VERSION 5.7 ;
BUSBITCHARS "[]" ;
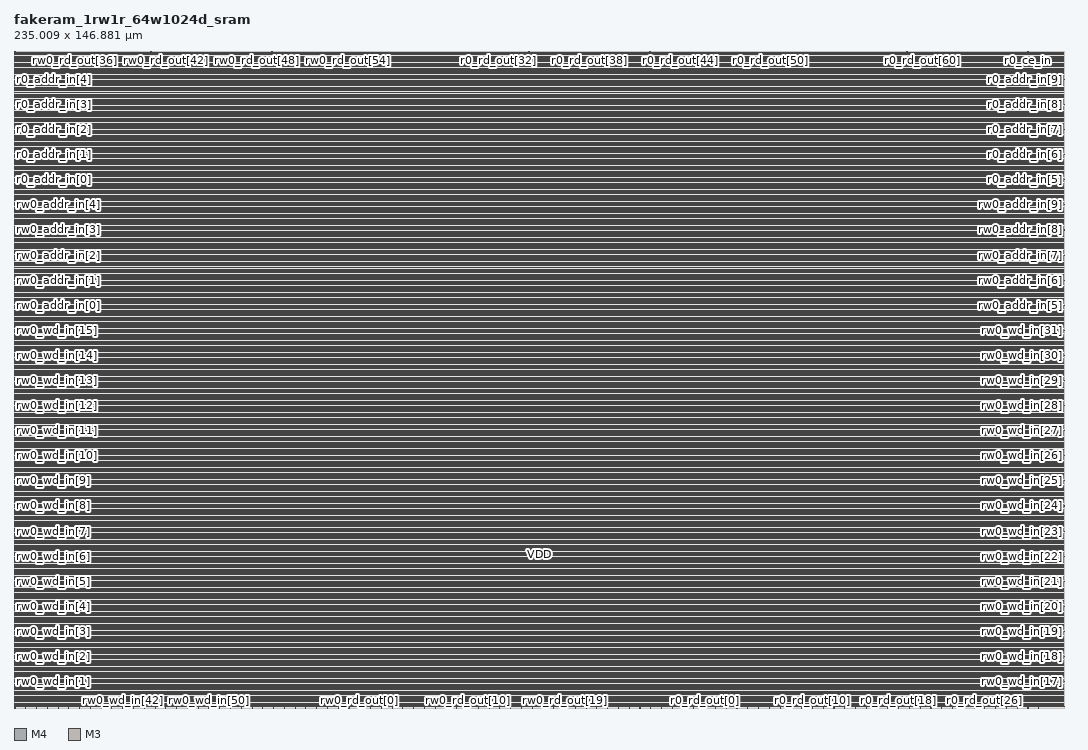
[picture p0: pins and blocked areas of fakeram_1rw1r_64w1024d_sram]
MACRO fakeram_1rw1r_64w1024d_sram
  FOREIGN fakeram_1rw1r_64w1024d_sram 0 0 ;
  SYMMETRY X Y R90 ;
  SIZE 235.009 BY 146.881 ;
  CLASS BLOCK ;
  PIN rw0_wd_in[0]
    DIRECTION INPUT ;
    USE SIGNAL ;
    SHAPE ABUTMENT ;
    PORT
      LAYER M4 ;
      RECT 0.000 0.276 0.072 0.300 ;
    END
  END rw0_wd_in[0]
  PIN rw0_wd_in[1]
    DIRECTION INPUT ;
    USE SIGNAL ;
    SHAPE ABUTMENT ;
    PORT
      LAYER M4 ;
      RECT 0.000 5.892 0.072 5.916 ;
    END
  END rw0_wd_in[1]
  PIN rw0_wd_in[2]
    DIRECTION INPUT ;
    USE SIGNAL ;
    SHAPE ABUTMENT ;
    PORT
      LAYER M4 ;
      RECT 0.000 11.508 0.072 11.532 ;
    END
  END rw0_wd_in[2]
  PIN rw0_wd_in[3]
    DIRECTION INPUT ;
    USE SIGNAL ;
    SHAPE ABUTMENT ;
    PORT
      LAYER M4 ;
      RECT 0.000 17.124 0.072 17.148 ;
    END
  END rw0_wd_in[3]
  PIN rw0_wd_in[4]
    DIRECTION INPUT ;
    USE SIGNAL ;
    SHAPE ABUTMENT ;
    PORT
      LAYER M4 ;
      RECT 0.000 22.740 0.072 22.764 ;
    END
  END rw0_wd_in[4]
  PIN rw0_wd_in[5]
    DIRECTION INPUT ;
    USE SIGNAL ;
    SHAPE ABUTMENT ;
    PORT
      LAYER M4 ;
      RECT 0.000 28.356 0.072 28.380 ;
    END
  END rw0_wd_in[5]
  PIN rw0_wd_in[6]
    DIRECTION INPUT ;
    USE SIGNAL ;
    SHAPE ABUTMENT ;
    PORT
      LAYER M4 ;
      RECT 0.000 33.972 0.072 33.996 ;
    END
  END rw0_wd_in[6]
  PIN rw0_wd_in[7]
    DIRECTION INPUT ;
    USE SIGNAL ;
    SHAPE ABUTMENT ;
    PORT
      LAYER M4 ;
      RECT 0.000 39.588 0.072 39.612 ;
    END
  END rw0_wd_in[7]
  PIN rw0_wd_in[8]
    DIRECTION INPUT ;
    USE SIGNAL ;
    SHAPE ABUTMENT ;
    PORT
      LAYER M4 ;
      RECT 0.000 45.204 0.072 45.228 ;
    END
  END rw0_wd_in[8]
  PIN rw0_wd_in[9]
    DIRECTION INPUT ;
    USE SIGNAL ;
    SHAPE ABUTMENT ;
    PORT
      LAYER M4 ;
      RECT 0.000 50.820 0.072 50.844 ;
    END
  END rw0_wd_in[9]
  PIN rw0_wd_in[10]
    DIRECTION INPUT ;
    USE SIGNAL ;
    SHAPE ABUTMENT ;
    PORT
      LAYER M4 ;
      RECT 0.000 56.436 0.072 56.460 ;
    END
  END rw0_wd_in[10]
  PIN rw0_wd_in[11]
    DIRECTION INPUT ;
    USE SIGNAL ;
    SHAPE ABUTMENT ;
    PORT
      LAYER M4 ;
      RECT 0.000 62.052 0.072 62.076 ;
    END
  END rw0_wd_in[11]
  PIN rw0_wd_in[12]
    DIRECTION INPUT ;
    USE SIGNAL ;
    SHAPE ABUTMENT ;
    PORT
      LAYER M4 ;
      RECT 0.000 67.668 0.072 67.692 ;
    END
  END rw0_wd_in[12]
  PIN rw0_wd_in[13]
    DIRECTION INPUT ;
    USE SIGNAL ;
    SHAPE ABUTMENT ;
    PORT
      LAYER M4 ;
      RECT 0.000 73.284 0.072 73.308 ;
    END
  END rw0_wd_in[13]
  PIN rw0_wd_in[14]
    DIRECTION INPUT ;
    USE SIGNAL ;
    SHAPE ABUTMENT ;
    PORT
      LAYER M4 ;
      RECT 0.000 78.900 0.072 78.924 ;
    END
  END rw0_wd_in[14]
  PIN rw0_wd_in[15]
    DIRECTION INPUT ;
    USE SIGNAL ;
    SHAPE ABUTMENT ;
    PORT
      LAYER M4 ;
      RECT 0.000 84.516 0.072 84.540 ;
    END
  END rw0_wd_in[15]
  PIN rw0_wd_in[16]
    DIRECTION INPUT ;
    USE SIGNAL ;
    SHAPE ABUTMENT ;
    PORT
      LAYER M4 ;
      RECT 234.937 0.276 235.009 0.300 ;
    END
  END rw0_wd_in[16]
  PIN rw0_wd_in[17]
    DIRECTION INPUT ;
    USE SIGNAL ;
    SHAPE ABUTMENT ;
    PORT
      LAYER M4 ;
      RECT 234.937 5.892 235.009 5.916 ;
    END
  END rw0_wd_in[17]
  PIN rw0_wd_in[18]
    DIRECTION INPUT ;
    USE SIGNAL ;
    SHAPE ABUTMENT ;
    PORT
      LAYER M4 ;
      RECT 234.937 11.508 235.009 11.532 ;
    END
  END rw0_wd_in[18]
  PIN rw0_wd_in[19]
    DIRECTION INPUT ;
    USE SIGNAL ;
    SHAPE ABUTMENT ;
    PORT
      LAYER M4 ;
      RECT 234.937 17.124 235.009 17.148 ;
    END
  END rw0_wd_in[19]
  PIN rw0_wd_in[20]
    DIRECTION INPUT ;
    USE SIGNAL ;
    SHAPE ABUTMENT ;
    PORT
      LAYER M4 ;
      RECT 234.937 22.740 235.009 22.764 ;
    END
  END rw0_wd_in[20]
  PIN rw0_wd_in[21]
    DIRECTION INPUT ;
    USE SIGNAL ;
    SHAPE ABUTMENT ;
    PORT
      LAYER M4 ;
      RECT 234.937 28.356 235.009 28.380 ;
    END
  END rw0_wd_in[21]
  PIN rw0_wd_in[22]
    DIRECTION INPUT ;
    USE SIGNAL ;
    SHAPE ABUTMENT ;
    PORT
      LAYER M4 ;
      RECT 234.937 33.972 235.009 33.996 ;
    END
  END rw0_wd_in[22]
  PIN rw0_wd_in[23]
    DIRECTION INPUT ;
    USE SIGNAL ;
    SHAPE ABUTMENT ;
    PORT
      LAYER M4 ;
      RECT 234.937 39.588 235.009 39.612 ;
    END
  END rw0_wd_in[23]
  PIN rw0_wd_in[24]
    DIRECTION INPUT ;
    USE SIGNAL ;
    SHAPE ABUTMENT ;
    PORT
      LAYER M4 ;
      RECT 234.937 45.204 235.009 45.228 ;
    END
  END rw0_wd_in[24]
  PIN rw0_wd_in[25]
    DIRECTION INPUT ;
    USE SIGNAL ;
    SHAPE ABUTMENT ;
    PORT
      LAYER M4 ;
      RECT 234.937 50.820 235.009 50.844 ;
    END
  END rw0_wd_in[25]
  PIN rw0_wd_in[26]
    DIRECTION INPUT ;
    USE SIGNAL ;
    SHAPE ABUTMENT ;
    PORT
      LAYER M4 ;
      RECT 234.937 56.436 235.009 56.460 ;
    END
  END rw0_wd_in[26]
  PIN rw0_wd_in[27]
    DIRECTION INPUT ;
    USE SIGNAL ;
    SHAPE ABUTMENT ;
    PORT
      LAYER M4 ;
      RECT 234.937 62.052 235.009 62.076 ;
    END
  END rw0_wd_in[27]
  PIN rw0_wd_in[28]
    DIRECTION INPUT ;
    USE SIGNAL ;
    SHAPE ABUTMENT ;
    PORT
      LAYER M4 ;
      RECT 234.937 67.668 235.009 67.692 ;
    END
  END rw0_wd_in[28]
  PIN rw0_wd_in[29]
    DIRECTION INPUT ;
    USE SIGNAL ;
    SHAPE ABUTMENT ;
    PORT
      LAYER M4 ;
      RECT 234.937 73.284 235.009 73.308 ;
    END
  END rw0_wd_in[29]
  PIN rw0_wd_in[30]
    DIRECTION INPUT ;
    USE SIGNAL ;
    SHAPE ABUTMENT ;
    PORT
      LAYER M4 ;
      RECT 234.937 78.900 235.009 78.924 ;
    END
  END rw0_wd_in[30]
  PIN rw0_wd_in[31]
    DIRECTION INPUT ;
    USE SIGNAL ;
    SHAPE ABUTMENT ;
    PORT
      LAYER M4 ;
      RECT 234.937 84.516 235.009 84.540 ;
    END
  END rw0_wd_in[31]
  PIN rw0_wd_in[32]
    DIRECTION INPUT ;
    USE SIGNAL ;
    SHAPE ABUTMENT ;
    PORT
      LAYER M3 ;
      RECT 0.207 0.000 0.225 0.054 ;
    END
  END rw0_wd_in[32]
  PIN rw0_wd_in[33]
    DIRECTION INPUT ;
    USE SIGNAL ;
    SHAPE ABUTMENT ;
    PORT
      LAYER M3 ;
      RECT 2.619 0.000 2.637 0.054 ;
    END
  END rw0_wd_in[33]
  PIN rw0_wd_in[34]
    DIRECTION INPUT ;
    USE SIGNAL ;
    SHAPE ABUTMENT ;
    PORT
      LAYER M3 ;
      RECT 5.031 0.000 5.049 0.054 ;
    END
  END rw0_wd_in[34]
  PIN rw0_wd_in[35]
    DIRECTION INPUT ;
    USE SIGNAL ;
    SHAPE ABUTMENT ;
    PORT
      LAYER M3 ;
      RECT 7.443 0.000 7.461 0.054 ;
    END
  END rw0_wd_in[35]
  PIN rw0_wd_in[36]
    DIRECTION INPUT ;
    USE SIGNAL ;
    SHAPE ABUTMENT ;
    PORT
      LAYER M3 ;
      RECT 9.855 0.000 9.873 0.054 ;
    END
  END rw0_wd_in[36]
  PIN rw0_wd_in[37]
    DIRECTION INPUT ;
    USE SIGNAL ;
    SHAPE ABUTMENT ;
    PORT
      LAYER M3 ;
      RECT 12.267 0.000 12.285 0.054 ;
    END
  END rw0_wd_in[37]
  PIN rw0_wd_in[38]
    DIRECTION INPUT ;
    USE SIGNAL ;
    SHAPE ABUTMENT ;
    PORT
      LAYER M3 ;
      RECT 14.679 0.000 14.697 0.054 ;
    END
  END rw0_wd_in[38]
  PIN rw0_wd_in[39]
    DIRECTION INPUT ;
    USE SIGNAL ;
    SHAPE ABUTMENT ;
    PORT
      LAYER M3 ;
      RECT 17.091 0.000 17.109 0.054 ;
    END
  END rw0_wd_in[39]
  PIN rw0_wd_in[40]
    DIRECTION INPUT ;
    USE SIGNAL ;
    SHAPE ABUTMENT ;
    PORT
      LAYER M3 ;
      RECT 19.503 0.000 19.521 0.054 ;
    END
  END rw0_wd_in[40]
  PIN rw0_wd_in[41]
    DIRECTION INPUT ;
    USE SIGNAL ;
    SHAPE ABUTMENT ;
    PORT
      LAYER M3 ;
      RECT 21.915 0.000 21.933 0.054 ;
    END
  END rw0_wd_in[41]
  PIN rw0_wd_in[42]
    DIRECTION INPUT ;
    USE SIGNAL ;
    SHAPE ABUTMENT ;
    PORT
      LAYER M3 ;
      RECT 24.327 0.000 24.345 0.054 ;
    END
  END rw0_wd_in[42]
  PIN rw0_wd_in[43]
    DIRECTION INPUT ;
    USE SIGNAL ;
    SHAPE ABUTMENT ;
    PORT
      LAYER M3 ;
      RECT 26.739 0.000 26.757 0.054 ;
    END
  END rw0_wd_in[43]
  PIN rw0_wd_in[44]
    DIRECTION INPUT ;
    USE SIGNAL ;
    SHAPE ABUTMENT ;
    PORT
      LAYER M3 ;
      RECT 29.151 0.000 29.169 0.054 ;
    END
  END rw0_wd_in[44]
  PIN rw0_wd_in[45]
    DIRECTION INPUT ;
    USE SIGNAL ;
    SHAPE ABUTMENT ;
    PORT
      LAYER M3 ;
      RECT 31.563 0.000 31.581 0.054 ;
    END
  END rw0_wd_in[45]
  PIN rw0_wd_in[46]
    DIRECTION INPUT ;
    USE SIGNAL ;
    SHAPE ABUTMENT ;
    PORT
      LAYER M3 ;
      RECT 33.975 0.000 33.993 0.054 ;
    END
  END rw0_wd_in[46]
  PIN rw0_wd_in[47]
    DIRECTION INPUT ;
    USE SIGNAL ;
    SHAPE ABUTMENT ;
    PORT
      LAYER M3 ;
      RECT 36.387 0.000 36.405 0.054 ;
    END
  END rw0_wd_in[47]
  PIN rw0_wd_in[48]
    DIRECTION INPUT ;
    USE SIGNAL ;
    SHAPE ABUTMENT ;
    PORT
      LAYER M3 ;
      RECT 38.799 0.000 38.817 0.054 ;
    END
  END rw0_wd_in[48]
  PIN rw0_wd_in[49]
    DIRECTION INPUT ;
    USE SIGNAL ;
    SHAPE ABUTMENT ;
    PORT
      LAYER M3 ;
      RECT 41.211 0.000 41.229 0.054 ;
    END
  END rw0_wd_in[49]
  PIN rw0_wd_in[50]
    DIRECTION INPUT ;
    USE SIGNAL ;
    SHAPE ABUTMENT ;
    PORT
      LAYER M3 ;
      RECT 43.623 0.000 43.641 0.054 ;
    END
  END rw0_wd_in[50]
  PIN rw0_wd_in[51]
    DIRECTION INPUT ;
    USE SIGNAL ;
    SHAPE ABUTMENT ;
    PORT
      LAYER M3 ;
      RECT 46.035 0.000 46.053 0.054 ;
    END
  END rw0_wd_in[51]
  PIN rw0_wd_in[52]
    DIRECTION INPUT ;
    USE SIGNAL ;
    SHAPE ABUTMENT ;
    PORT
      LAYER M3 ;
      RECT 48.447 0.000 48.465 0.054 ;
    END
  END rw0_wd_in[52]
  PIN rw0_wd_in[53]
    DIRECTION INPUT ;
    USE SIGNAL ;
    SHAPE ABUTMENT ;
    PORT
      LAYER M3 ;
      RECT 50.859 0.000 50.877 0.054 ;
    END
  END rw0_wd_in[53]
  PIN rw0_wd_in[54]
    DIRECTION INPUT ;
    USE SIGNAL ;
    SHAPE ABUTMENT ;
    PORT
      LAYER M3 ;
      RECT 53.271 0.000 53.289 0.054 ;
    END
  END rw0_wd_in[54]
  PIN rw0_wd_in[55]
    DIRECTION INPUT ;
    USE SIGNAL ;
    SHAPE ABUTMENT ;
    PORT
      LAYER M3 ;
      RECT 55.683 0.000 55.701 0.054 ;
    END
  END rw0_wd_in[55]
  PIN rw0_wd_in[56]
    DIRECTION INPUT ;
    USE SIGNAL ;
    SHAPE ABUTMENT ;
    PORT
      LAYER M3 ;
      RECT 58.095 0.000 58.113 0.054 ;
    END
  END rw0_wd_in[56]
  PIN rw0_wd_in[57]
    DIRECTION INPUT ;
    USE SIGNAL ;
    SHAPE ABUTMENT ;
    PORT
      LAYER M3 ;
      RECT 60.507 0.000 60.525 0.054 ;
    END
  END rw0_wd_in[57]
  PIN rw0_wd_in[58]
    DIRECTION INPUT ;
    USE SIGNAL ;
    SHAPE ABUTMENT ;
    PORT
      LAYER M3 ;
      RECT 62.919 0.000 62.937 0.054 ;
    END
  END rw0_wd_in[58]
  PIN rw0_wd_in[59]
    DIRECTION INPUT ;
    USE SIGNAL ;
    SHAPE ABUTMENT ;
    PORT
      LAYER M3 ;
      RECT 65.331 0.000 65.349 0.054 ;
    END
  END rw0_wd_in[59]
  PIN rw0_wd_in[60]
    DIRECTION INPUT ;
    USE SIGNAL ;
    SHAPE ABUTMENT ;
    PORT
      LAYER M3 ;
      RECT 67.743 0.000 67.761 0.054 ;
    END
  END rw0_wd_in[60]
  PIN rw0_wd_in[61]
    DIRECTION INPUT ;
    USE SIGNAL ;
    SHAPE ABUTMENT ;
    PORT
      LAYER M3 ;
      RECT 70.155 0.000 70.173 0.054 ;
    END
  END rw0_wd_in[61]
  PIN rw0_wd_in[62]
    DIRECTION INPUT ;
    USE SIGNAL ;
    SHAPE ABUTMENT ;
    PORT
      LAYER M3 ;
      RECT 72.567 0.000 72.585 0.054 ;
    END
  END rw0_wd_in[62]
  PIN rw0_wd_in[63]
    DIRECTION INPUT ;
    USE SIGNAL ;
    SHAPE ABUTMENT ;
    PORT
      LAYER M3 ;
      RECT 74.979 0.000 74.997 0.054 ;
    END
  END rw0_wd_in[63]
  PIN rw0_rd_out[0]
    DIRECTION OUTPUT ;
    USE SIGNAL ;
    SHAPE ABUTMENT ;
    PORT
      LAYER M3 ;
      RECT 77.391 0.000 77.409 0.054 ;
    END
  END rw0_rd_out[0]
  PIN rw0_rd_out[1]
    DIRECTION OUTPUT ;
    USE SIGNAL ;
    SHAPE ABUTMENT ;
    PORT
      LAYER M3 ;
      RECT 79.803 0.000 79.821 0.054 ;
    END
  END rw0_rd_out[1]
  PIN rw0_rd_out[2]
    DIRECTION OUTPUT ;
    USE SIGNAL ;
    SHAPE ABUTMENT ;
    PORT
      LAYER M3 ;
      RECT 82.215 0.000 82.233 0.054 ;
    END
  END rw0_rd_out[2]
  PIN rw0_rd_out[3]
    DIRECTION OUTPUT ;
    USE SIGNAL ;
    SHAPE ABUTMENT ;
    PORT
      LAYER M3 ;
      RECT 84.627 0.000 84.645 0.054 ;
    END
  END rw0_rd_out[3]
  PIN rw0_rd_out[4]
    DIRECTION OUTPUT ;
    USE SIGNAL ;
    SHAPE ABUTMENT ;
    PORT
      LAYER M3 ;
      RECT 87.039 0.000 87.057 0.054 ;
    END
  END rw0_rd_out[4]
  PIN rw0_rd_out[5]
    DIRECTION OUTPUT ;
    USE SIGNAL ;
    SHAPE ABUTMENT ;
    PORT
      LAYER M3 ;
      RECT 89.451 0.000 89.469 0.054 ;
    END
  END rw0_rd_out[5]
  PIN rw0_rd_out[6]
    DIRECTION OUTPUT ;
    USE SIGNAL ;
    SHAPE ABUTMENT ;
    PORT
      LAYER M3 ;
      RECT 91.863 0.000 91.881 0.054 ;
    END
  END rw0_rd_out[6]
  PIN rw0_rd_out[7]
    DIRECTION OUTPUT ;
    USE SIGNAL ;
    SHAPE ABUTMENT ;
    PORT
      LAYER M3 ;
      RECT 94.275 0.000 94.293 0.054 ;
    END
  END rw0_rd_out[7]
  PIN rw0_rd_out[8]
    DIRECTION OUTPUT ;
    USE SIGNAL ;
    SHAPE ABUTMENT ;
    PORT
      LAYER M3 ;
      RECT 96.687 0.000 96.705 0.054 ;
    END
  END rw0_rd_out[8]
  PIN rw0_rd_out[9]
    DIRECTION OUTPUT ;
    USE SIGNAL ;
    SHAPE ABUTMENT ;
    PORT
      LAYER M3 ;
      RECT 99.099 0.000 99.117 0.054 ;
    END
  END rw0_rd_out[9]
  PIN rw0_rd_out[10]
    DIRECTION OUTPUT ;
    USE SIGNAL ;
    SHAPE ABUTMENT ;
    PORT
      LAYER M3 ;
      RECT 101.511 0.000 101.529 0.054 ;
    END
  END rw0_rd_out[10]
  PIN rw0_rd_out[11]
    DIRECTION OUTPUT ;
    USE SIGNAL ;
    SHAPE ABUTMENT ;
    PORT
      LAYER M3 ;
      RECT 103.923 0.000 103.941 0.054 ;
    END
  END rw0_rd_out[11]
  PIN rw0_rd_out[12]
    DIRECTION OUTPUT ;
    USE SIGNAL ;
    SHAPE ABUTMENT ;
    PORT
      LAYER M3 ;
      RECT 106.335 0.000 106.353 0.054 ;
    END
  END rw0_rd_out[12]
  PIN rw0_rd_out[13]
    DIRECTION OUTPUT ;
    USE SIGNAL ;
    SHAPE ABUTMENT ;
    PORT
      LAYER M3 ;
      RECT 108.747 0.000 108.765 0.054 ;
    END
  END rw0_rd_out[13]
  PIN rw0_rd_out[14]
    DIRECTION OUTPUT ;
    USE SIGNAL ;
    SHAPE ABUTMENT ;
    PORT
      LAYER M3 ;
      RECT 111.159 0.000 111.177 0.054 ;
    END
  END rw0_rd_out[14]
  PIN rw0_rd_out[15]
    DIRECTION OUTPUT ;
    USE SIGNAL ;
    SHAPE ABUTMENT ;
    PORT
      LAYER M3 ;
      RECT 113.571 0.000 113.589 0.054 ;
    END
  END rw0_rd_out[15]
  PIN rw0_rd_out[16]
    DIRECTION OUTPUT ;
    USE SIGNAL ;
    SHAPE ABUTMENT ;
    PORT
      LAYER M3 ;
      RECT 115.983 0.000 116.001 0.054 ;
    END
  END rw0_rd_out[16]
  PIN rw0_rd_out[17]
    DIRECTION OUTPUT ;
    USE SIGNAL ;
    SHAPE ABUTMENT ;
    PORT
      LAYER M3 ;
      RECT 118.395 0.000 118.413 0.054 ;
    END
  END rw0_rd_out[17]
  PIN rw0_rd_out[18]
    DIRECTION OUTPUT ;
    USE SIGNAL ;
    SHAPE ABUTMENT ;
    PORT
      LAYER M3 ;
      RECT 120.807 0.000 120.825 0.054 ;
    END
  END rw0_rd_out[18]
  PIN rw0_rd_out[19]
    DIRECTION OUTPUT ;
    USE SIGNAL ;
    SHAPE ABUTMENT ;
    PORT
      LAYER M3 ;
      RECT 123.219 0.000 123.237 0.054 ;
    END
  END rw0_rd_out[19]
  PIN rw0_rd_out[20]
    DIRECTION OUTPUT ;
    USE SIGNAL ;
    SHAPE ABUTMENT ;
    PORT
      LAYER M3 ;
      RECT 125.631 0.000 125.649 0.054 ;
    END
  END rw0_rd_out[20]
  PIN rw0_rd_out[21]
    DIRECTION OUTPUT ;
    USE SIGNAL ;
    SHAPE ABUTMENT ;
    PORT
      LAYER M3 ;
      RECT 128.043 0.000 128.061 0.054 ;
    END
  END rw0_rd_out[21]
  PIN rw0_rd_out[22]
    DIRECTION OUTPUT ;
    USE SIGNAL ;
    SHAPE ABUTMENT ;
    PORT
      LAYER M3 ;
      RECT 130.455 0.000 130.473 0.054 ;
    END
  END rw0_rd_out[22]
  PIN rw0_rd_out[23]
    DIRECTION OUTPUT ;
    USE SIGNAL ;
    SHAPE ABUTMENT ;
    PORT
      LAYER M3 ;
      RECT 132.867 0.000 132.885 0.054 ;
    END
  END rw0_rd_out[23]
  PIN rw0_rd_out[24]
    DIRECTION OUTPUT ;
    USE SIGNAL ;
    SHAPE ABUTMENT ;
    PORT
      LAYER M3 ;
      RECT 135.279 0.000 135.297 0.054 ;
    END
  END rw0_rd_out[24]
  PIN rw0_rd_out[25]
    DIRECTION OUTPUT ;
    USE SIGNAL ;
    SHAPE ABUTMENT ;
    PORT
      LAYER M3 ;
      RECT 137.691 0.000 137.709 0.054 ;
    END
  END rw0_rd_out[25]
  PIN rw0_rd_out[26]
    DIRECTION OUTPUT ;
    USE SIGNAL ;
    SHAPE ABUTMENT ;
    PORT
      LAYER M3 ;
      RECT 140.103 0.000 140.121 0.054 ;
    END
  END rw0_rd_out[26]
  PIN rw0_rd_out[27]
    DIRECTION OUTPUT ;
    USE SIGNAL ;
    SHAPE ABUTMENT ;
    PORT
      LAYER M3 ;
      RECT 142.515 0.000 142.533 0.054 ;
    END
  END rw0_rd_out[27]
  PIN rw0_rd_out[28]
    DIRECTION OUTPUT ;
    USE SIGNAL ;
    SHAPE ABUTMENT ;
    PORT
      LAYER M3 ;
      RECT 144.927 0.000 144.945 0.054 ;
    END
  END rw0_rd_out[28]
  PIN rw0_rd_out[29]
    DIRECTION OUTPUT ;
    USE SIGNAL ;
    SHAPE ABUTMENT ;
    PORT
      LAYER M3 ;
      RECT 147.339 0.000 147.357 0.054 ;
    END
  END rw0_rd_out[29]
  PIN rw0_rd_out[30]
    DIRECTION OUTPUT ;
    USE SIGNAL ;
    SHAPE ABUTMENT ;
    PORT
      LAYER M3 ;
      RECT 149.751 0.000 149.769 0.054 ;
    END
  END rw0_rd_out[30]
  PIN rw0_rd_out[31]
    DIRECTION OUTPUT ;
    USE SIGNAL ;
    SHAPE ABUTMENT ;
    PORT
      LAYER M3 ;
      RECT 152.163 0.000 152.181 0.054 ;
    END
  END rw0_rd_out[31]
  PIN rw0_rd_out[32]
    DIRECTION OUTPUT ;
    USE SIGNAL ;
    SHAPE ABUTMENT ;
    PORT
      LAYER M3 ;
      RECT 0.207 146.827 0.225 146.881 ;
    END
  END rw0_rd_out[32]
  PIN rw0_rd_out[33]
    DIRECTION OUTPUT ;
    USE SIGNAL ;
    SHAPE ABUTMENT ;
    PORT
      LAYER M3 ;
      RECT 3.591 146.827 3.609 146.881 ;
    END
  END rw0_rd_out[33]
  PIN rw0_rd_out[34]
    DIRECTION OUTPUT ;
    USE SIGNAL ;
    SHAPE ABUTMENT ;
    PORT
      LAYER M3 ;
      RECT 6.975 146.827 6.993 146.881 ;
    END
  END rw0_rd_out[34]
  PIN rw0_rd_out[35]
    DIRECTION OUTPUT ;
    USE SIGNAL ;
    SHAPE ABUTMENT ;
    PORT
      LAYER M3 ;
      RECT 10.359 146.827 10.377 146.881 ;
    END
  END rw0_rd_out[35]
  PIN rw0_rd_out[36]
    DIRECTION OUTPUT ;
    USE SIGNAL ;
    SHAPE ABUTMENT ;
    PORT
      LAYER M3 ;
      RECT 13.743 146.827 13.761 146.881 ;
    END
  END rw0_rd_out[36]
  PIN rw0_rd_out[37]
    DIRECTION OUTPUT ;
    USE SIGNAL ;
    SHAPE ABUTMENT ;
    PORT
      LAYER M3 ;
      RECT 17.127 146.827 17.145 146.881 ;
    END
  END rw0_rd_out[37]
  PIN rw0_rd_out[38]
    DIRECTION OUTPUT ;
    USE SIGNAL ;
    SHAPE ABUTMENT ;
    PORT
      LAYER M3 ;
      RECT 20.511 146.827 20.529 146.881 ;
    END
  END rw0_rd_out[38]
  PIN rw0_rd_out[39]
    DIRECTION OUTPUT ;
    USE SIGNAL ;
    SHAPE ABUTMENT ;
    PORT
      LAYER M3 ;
      RECT 23.895 146.827 23.913 146.881 ;
    END
  END rw0_rd_out[39]
  PIN rw0_rd_out[40]
    DIRECTION OUTPUT ;
    USE SIGNAL ;
    SHAPE ABUTMENT ;
    PORT
      LAYER M3 ;
      RECT 27.279 146.827 27.297 146.881 ;
    END
  END rw0_rd_out[40]
  PIN rw0_rd_out[41]
    DIRECTION OUTPUT ;
    USE SIGNAL ;
    SHAPE ABUTMENT ;
    PORT
      LAYER M3 ;
      RECT 30.663 146.827 30.681 146.881 ;
    END
  END rw0_rd_out[41]
  PIN rw0_rd_out[42]
    DIRECTION OUTPUT ;
    USE SIGNAL ;
    SHAPE ABUTMENT ;
    PORT
      LAYER M3 ;
      RECT 34.047 146.827 34.065 146.881 ;
    END
  END rw0_rd_out[42]
  PIN rw0_rd_out[43]
    DIRECTION OUTPUT ;
    USE SIGNAL ;
    SHAPE ABUTMENT ;
    PORT
      LAYER M3 ;
      RECT 37.431 146.827 37.449 146.881 ;
    END
  END rw0_rd_out[43]
  PIN rw0_rd_out[44]
    DIRECTION OUTPUT ;
    USE SIGNAL ;
    SHAPE ABUTMENT ;
    PORT
      LAYER M3 ;
      RECT 40.815 146.827 40.833 146.881 ;
    END
  END rw0_rd_out[44]
  PIN rw0_rd_out[45]
    DIRECTION OUTPUT ;
    USE SIGNAL ;
    SHAPE ABUTMENT ;
    PORT
      LAYER M3 ;
      RECT 44.199 146.827 44.217 146.881 ;
    END
  END rw0_rd_out[45]
  PIN rw0_rd_out[46]
    DIRECTION OUTPUT ;
    USE SIGNAL ;
    SHAPE ABUTMENT ;
    PORT
      LAYER M3 ;
      RECT 47.583 146.827 47.601 146.881 ;
    END
  END rw0_rd_out[46]
  PIN rw0_rd_out[47]
    DIRECTION OUTPUT ;
    USE SIGNAL ;
    SHAPE ABUTMENT ;
    PORT
      LAYER M3 ;
      RECT 50.967 146.827 50.985 146.881 ;
    END
  END rw0_rd_out[47]
  PIN rw0_rd_out[48]
    DIRECTION OUTPUT ;
    USE SIGNAL ;
    SHAPE ABUTMENT ;
    PORT
      LAYER M3 ;
      RECT 54.351 146.827 54.369 146.881 ;
    END
  END rw0_rd_out[48]
  PIN rw0_rd_out[49]
    DIRECTION OUTPUT ;
    USE SIGNAL ;
    SHAPE ABUTMENT ;
    PORT
      LAYER M3 ;
      RECT 57.735 146.827 57.753 146.881 ;
    END
  END rw0_rd_out[49]
  PIN rw0_rd_out[50]
    DIRECTION OUTPUT ;
    USE SIGNAL ;
    SHAPE ABUTMENT ;
    PORT
      LAYER M3 ;
      RECT 61.119 146.827 61.137 146.881 ;
    END
  END rw0_rd_out[50]
  PIN rw0_rd_out[51]
    DIRECTION OUTPUT ;
    USE SIGNAL ;
    SHAPE ABUTMENT ;
    PORT
      LAYER M3 ;
      RECT 64.503 146.827 64.521 146.881 ;
    END
  END rw0_rd_out[51]
  PIN rw0_rd_out[52]
    DIRECTION OUTPUT ;
    USE SIGNAL ;
    SHAPE ABUTMENT ;
    PORT
      LAYER M3 ;
      RECT 67.887 146.827 67.905 146.881 ;
    END
  END rw0_rd_out[52]
  PIN rw0_rd_out[53]
    DIRECTION OUTPUT ;
    USE SIGNAL ;
    SHAPE ABUTMENT ;
    PORT
      LAYER M3 ;
      RECT 71.271 146.827 71.289 146.881 ;
    END
  END rw0_rd_out[53]
  PIN rw0_rd_out[54]
    DIRECTION OUTPUT ;
    USE SIGNAL ;
    SHAPE ABUTMENT ;
    PORT
      LAYER M3 ;
      RECT 74.655 146.827 74.673 146.881 ;
    END
  END rw0_rd_out[54]
  PIN rw0_rd_out[55]
    DIRECTION OUTPUT ;
    USE SIGNAL ;
    SHAPE ABUTMENT ;
    PORT
      LAYER M3 ;
      RECT 78.039 146.827 78.057 146.881 ;
    END
  END rw0_rd_out[55]
  PIN rw0_rd_out[56]
    DIRECTION OUTPUT ;
    USE SIGNAL ;
    SHAPE ABUTMENT ;
    PORT
      LAYER M3 ;
      RECT 81.423 146.827 81.441 146.881 ;
    END
  END rw0_rd_out[56]
  PIN rw0_rd_out[57]
    DIRECTION OUTPUT ;
    USE SIGNAL ;
    SHAPE ABUTMENT ;
    PORT
      LAYER M3 ;
      RECT 84.807 146.827 84.825 146.881 ;
    END
  END rw0_rd_out[57]
  PIN rw0_rd_out[58]
    DIRECTION OUTPUT ;
    USE SIGNAL ;
    SHAPE ABUTMENT ;
    PORT
      LAYER M3 ;
      RECT 88.191 146.827 88.209 146.881 ;
    END
  END rw0_rd_out[58]
  PIN rw0_rd_out[59]
    DIRECTION OUTPUT ;
    USE SIGNAL ;
    SHAPE ABUTMENT ;
    PORT
      LAYER M3 ;
      RECT 91.575 146.827 91.593 146.881 ;
    END
  END rw0_rd_out[59]
  PIN rw0_rd_out[60]
    DIRECTION OUTPUT ;
    USE SIGNAL ;
    SHAPE ABUTMENT ;
    PORT
      LAYER M3 ;
      RECT 94.959 146.827 94.977 146.881 ;
    END
  END rw0_rd_out[60]
  PIN rw0_rd_out[61]
    DIRECTION OUTPUT ;
    USE SIGNAL ;
    SHAPE ABUTMENT ;
    PORT
      LAYER M3 ;
      RECT 98.343 146.827 98.361 146.881 ;
    END
  END rw0_rd_out[61]
  PIN rw0_rd_out[62]
    DIRECTION OUTPUT ;
    USE SIGNAL ;
    SHAPE ABUTMENT ;
    PORT
      LAYER M3 ;
      RECT 101.727 146.827 101.745 146.881 ;
    END
  END rw0_rd_out[62]
  PIN rw0_rd_out[63]
    DIRECTION OUTPUT ;
    USE SIGNAL ;
    SHAPE ABUTMENT ;
    PORT
      LAYER M3 ;
      RECT 105.111 146.827 105.129 146.881 ;
    END
  END rw0_rd_out[63]
  PIN r0_rd_out[0]
    DIRECTION OUTPUT ;
    USE SIGNAL ;
    SHAPE ABUTMENT ;
    PORT
      LAYER M3 ;
      RECT 154.575 0.000 154.593 0.054 ;
    END
  END r0_rd_out[0]
  PIN r0_rd_out[1]
    DIRECTION OUTPUT ;
    USE SIGNAL ;
    SHAPE ABUTMENT ;
    PORT
      LAYER M3 ;
      RECT 156.987 0.000 157.005 0.054 ;
    END
  END r0_rd_out[1]
  PIN r0_rd_out[2]
    DIRECTION OUTPUT ;
    USE SIGNAL ;
    SHAPE ABUTMENT ;
    PORT
      LAYER M3 ;
      RECT 159.399 0.000 159.417 0.054 ;
    END
  END r0_rd_out[2]
  PIN r0_rd_out[3]
    DIRECTION OUTPUT ;
    USE SIGNAL ;
    SHAPE ABUTMENT ;
    PORT
      LAYER M3 ;
      RECT 161.811 0.000 161.829 0.054 ;
    END
  END r0_rd_out[3]
  PIN r0_rd_out[4]
    DIRECTION OUTPUT ;
    USE SIGNAL ;
    SHAPE ABUTMENT ;
    PORT
      LAYER M3 ;
      RECT 164.223 0.000 164.241 0.054 ;
    END
  END r0_rd_out[4]
  PIN r0_rd_out[5]
    DIRECTION OUTPUT ;
    USE SIGNAL ;
    SHAPE ABUTMENT ;
    PORT
      LAYER M3 ;
      RECT 166.635 0.000 166.653 0.054 ;
    END
  END r0_rd_out[5]
  PIN r0_rd_out[6]
    DIRECTION OUTPUT ;
    USE SIGNAL ;
    SHAPE ABUTMENT ;
    PORT
      LAYER M3 ;
      RECT 169.047 0.000 169.065 0.054 ;
    END
  END r0_rd_out[6]
  PIN r0_rd_out[7]
    DIRECTION OUTPUT ;
    USE SIGNAL ;
    SHAPE ABUTMENT ;
    PORT
      LAYER M3 ;
      RECT 171.459 0.000 171.477 0.054 ;
    END
  END r0_rd_out[7]
  PIN r0_rd_out[8]
    DIRECTION OUTPUT ;
    USE SIGNAL ;
    SHAPE ABUTMENT ;
    PORT
      LAYER M3 ;
      RECT 173.871 0.000 173.889 0.054 ;
    END
  END r0_rd_out[8]
  PIN r0_rd_out[9]
    DIRECTION OUTPUT ;
    USE SIGNAL ;
    SHAPE ABUTMENT ;
    PORT
      LAYER M3 ;
      RECT 176.283 0.000 176.301 0.054 ;
    END
  END r0_rd_out[9]
  PIN r0_rd_out[10]
    DIRECTION OUTPUT ;
    USE SIGNAL ;
    SHAPE ABUTMENT ;
    PORT
      LAYER M3 ;
      RECT 178.695 0.000 178.713 0.054 ;
    END
  END r0_rd_out[10]
  PIN r0_rd_out[11]
    DIRECTION OUTPUT ;
    USE SIGNAL ;
    SHAPE ABUTMENT ;
    PORT
      LAYER M3 ;
      RECT 181.107 0.000 181.125 0.054 ;
    END
  END r0_rd_out[11]
  PIN r0_rd_out[12]
    DIRECTION OUTPUT ;
    USE SIGNAL ;
    SHAPE ABUTMENT ;
    PORT
      LAYER M3 ;
      RECT 183.519 0.000 183.537 0.054 ;
    END
  END r0_rd_out[12]
  PIN r0_rd_out[13]
    DIRECTION OUTPUT ;
    USE SIGNAL ;
    SHAPE ABUTMENT ;
    PORT
      LAYER M3 ;
      RECT 185.931 0.000 185.949 0.054 ;
    END
  END r0_rd_out[13]
  PIN r0_rd_out[14]
    DIRECTION OUTPUT ;
    USE SIGNAL ;
    SHAPE ABUTMENT ;
    PORT
      LAYER M3 ;
      RECT 188.343 0.000 188.361 0.054 ;
    END
  END r0_rd_out[14]
  PIN r0_rd_out[15]
    DIRECTION OUTPUT ;
    USE SIGNAL ;
    SHAPE ABUTMENT ;
    PORT
      LAYER M3 ;
      RECT 190.755 0.000 190.773 0.054 ;
    END
  END r0_rd_out[15]
  PIN r0_rd_out[16]
    DIRECTION OUTPUT ;
    USE SIGNAL ;
    SHAPE ABUTMENT ;
    PORT
      LAYER M3 ;
      RECT 193.167 0.000 193.185 0.054 ;
    END
  END r0_rd_out[16]
  PIN r0_rd_out[17]
    DIRECTION OUTPUT ;
    USE SIGNAL ;
    SHAPE ABUTMENT ;
    PORT
      LAYER M3 ;
      RECT 195.579 0.000 195.597 0.054 ;
    END
  END r0_rd_out[17]
  PIN r0_rd_out[18]
    DIRECTION OUTPUT ;
    USE SIGNAL ;
    SHAPE ABUTMENT ;
    PORT
      LAYER M3 ;
      RECT 197.991 0.000 198.009 0.054 ;
    END
  END r0_rd_out[18]
  PIN r0_rd_out[19]
    DIRECTION OUTPUT ;
    USE SIGNAL ;
    SHAPE ABUTMENT ;
    PORT
      LAYER M3 ;
      RECT 200.403 0.000 200.421 0.054 ;
    END
  END r0_rd_out[19]
  PIN r0_rd_out[20]
    DIRECTION OUTPUT ;
    USE SIGNAL ;
    SHAPE ABUTMENT ;
    PORT
      LAYER M3 ;
      RECT 202.815 0.000 202.833 0.054 ;
    END
  END r0_rd_out[20]
  PIN r0_rd_out[21]
    DIRECTION OUTPUT ;
    USE SIGNAL ;
    SHAPE ABUTMENT ;
    PORT
      LAYER M3 ;
      RECT 205.227 0.000 205.245 0.054 ;
    END
  END r0_rd_out[21]
  PIN r0_rd_out[22]
    DIRECTION OUTPUT ;
    USE SIGNAL ;
    SHAPE ABUTMENT ;
    PORT
      LAYER M3 ;
      RECT 207.639 0.000 207.657 0.054 ;
    END
  END r0_rd_out[22]
  PIN r0_rd_out[23]
    DIRECTION OUTPUT ;
    USE SIGNAL ;
    SHAPE ABUTMENT ;
    PORT
      LAYER M3 ;
      RECT 210.051 0.000 210.069 0.054 ;
    END
  END r0_rd_out[23]
  PIN r0_rd_out[24]
    DIRECTION OUTPUT ;
    USE SIGNAL ;
    SHAPE ABUTMENT ;
    PORT
      LAYER M3 ;
      RECT 212.463 0.000 212.481 0.054 ;
    END
  END r0_rd_out[24]
  PIN r0_rd_out[25]
    DIRECTION OUTPUT ;
    USE SIGNAL ;
    SHAPE ABUTMENT ;
    PORT
      LAYER M3 ;
      RECT 214.875 0.000 214.893 0.054 ;
    END
  END r0_rd_out[25]
  PIN r0_rd_out[26]
    DIRECTION OUTPUT ;
    USE SIGNAL ;
    SHAPE ABUTMENT ;
    PORT
      LAYER M3 ;
      RECT 217.287 0.000 217.305 0.054 ;
    END
  END r0_rd_out[26]
  PIN r0_rd_out[27]
    DIRECTION OUTPUT ;
    USE SIGNAL ;
    SHAPE ABUTMENT ;
    PORT
      LAYER M3 ;
      RECT 219.699 0.000 219.717 0.054 ;
    END
  END r0_rd_out[27]
  PIN r0_rd_out[28]
    DIRECTION OUTPUT ;
    USE SIGNAL ;
    SHAPE ABUTMENT ;
    PORT
      LAYER M3 ;
      RECT 222.111 0.000 222.129 0.054 ;
    END
  END r0_rd_out[28]
  PIN r0_rd_out[29]
    DIRECTION OUTPUT ;
    USE SIGNAL ;
    SHAPE ABUTMENT ;
    PORT
      LAYER M3 ;
      RECT 224.523 0.000 224.541 0.054 ;
    END
  END r0_rd_out[29]
  PIN r0_rd_out[30]
    DIRECTION OUTPUT ;
    USE SIGNAL ;
    SHAPE ABUTMENT ;
    PORT
      LAYER M3 ;
      RECT 226.935 0.000 226.953 0.054 ;
    END
  END r0_rd_out[30]
  PIN r0_rd_out[31]
    DIRECTION OUTPUT ;
    USE SIGNAL ;
    SHAPE ABUTMENT ;
    PORT
      LAYER M3 ;
      RECT 229.347 0.000 229.365 0.054 ;
    END
  END r0_rd_out[31]
  PIN r0_rd_out[32]
    DIRECTION OUTPUT ;
    USE SIGNAL ;
    SHAPE ABUTMENT ;
    PORT
      LAYER M3 ;
      RECT 108.495 146.827 108.513 146.881 ;
    END
  END r0_rd_out[32]
  PIN r0_rd_out[33]
    DIRECTION OUTPUT ;
    USE SIGNAL ;
    SHAPE ABUTMENT ;
    PORT
      LAYER M3 ;
      RECT 111.879 146.827 111.897 146.881 ;
    END
  END r0_rd_out[33]
  PIN r0_rd_out[34]
    DIRECTION OUTPUT ;
    USE SIGNAL ;
    SHAPE ABUTMENT ;
    PORT
      LAYER M3 ;
      RECT 115.263 146.827 115.281 146.881 ;
    END
  END r0_rd_out[34]
  PIN r0_rd_out[35]
    DIRECTION OUTPUT ;
    USE SIGNAL ;
    SHAPE ABUTMENT ;
    PORT
      LAYER M3 ;
      RECT 118.647 146.827 118.665 146.881 ;
    END
  END r0_rd_out[35]
  PIN r0_rd_out[36]
    DIRECTION OUTPUT ;
    USE SIGNAL ;
    SHAPE ABUTMENT ;
    PORT
      LAYER M3 ;
      RECT 122.031 146.827 122.049 146.881 ;
    END
  END r0_rd_out[36]
  PIN r0_rd_out[37]
    DIRECTION OUTPUT ;
    USE SIGNAL ;
    SHAPE ABUTMENT ;
    PORT
      LAYER M3 ;
      RECT 125.415 146.827 125.433 146.881 ;
    END
  END r0_rd_out[37]
  PIN r0_rd_out[38]
    DIRECTION OUTPUT ;
    USE SIGNAL ;
    SHAPE ABUTMENT ;
    PORT
      LAYER M3 ;
      RECT 128.799 146.827 128.817 146.881 ;
    END
  END r0_rd_out[38]
  PIN r0_rd_out[39]
    DIRECTION OUTPUT ;
    USE SIGNAL ;
    SHAPE ABUTMENT ;
    PORT
      LAYER M3 ;
      RECT 132.183 146.827 132.201 146.881 ;
    END
  END r0_rd_out[39]
  PIN r0_rd_out[40]
    DIRECTION OUTPUT ;
    USE SIGNAL ;
    SHAPE ABUTMENT ;
    PORT
      LAYER M3 ;
      RECT 135.567 146.827 135.585 146.881 ;
    END
  END r0_rd_out[40]
  PIN r0_rd_out[41]
    DIRECTION OUTPUT ;
    USE SIGNAL ;
    SHAPE ABUTMENT ;
    PORT
      LAYER M3 ;
      RECT 138.951 146.827 138.969 146.881 ;
    END
  END r0_rd_out[41]
  PIN r0_rd_out[42]
    DIRECTION OUTPUT ;
    USE SIGNAL ;
    SHAPE ABUTMENT ;
    PORT
      LAYER M3 ;
      RECT 142.335 146.827 142.353 146.881 ;
    END
  END r0_rd_out[42]
  PIN r0_rd_out[43]
    DIRECTION OUTPUT ;
    USE SIGNAL ;
    SHAPE ABUTMENT ;
    PORT
      LAYER M3 ;
      RECT 145.719 146.827 145.737 146.881 ;
    END
  END r0_rd_out[43]
  PIN r0_rd_out[44]
    DIRECTION OUTPUT ;
    USE SIGNAL ;
    SHAPE ABUTMENT ;
    PORT
      LAYER M3 ;
      RECT 149.103 146.827 149.121 146.881 ;
    END
  END r0_rd_out[44]
  PIN r0_rd_out[45]
    DIRECTION OUTPUT ;
    USE SIGNAL ;
    SHAPE ABUTMENT ;
    PORT
      LAYER M3 ;
      RECT 152.487 146.827 152.505 146.881 ;
    END
  END r0_rd_out[45]
  PIN r0_rd_out[46]
    DIRECTION OUTPUT ;
    USE SIGNAL ;
    SHAPE ABUTMENT ;
    PORT
      LAYER M3 ;
      RECT 155.871 146.827 155.889 146.881 ;
    END
  END r0_rd_out[46]
  PIN r0_rd_out[47]
    DIRECTION OUTPUT ;
    USE SIGNAL ;
    SHAPE ABUTMENT ;
    PORT
      LAYER M3 ;
      RECT 159.255 146.827 159.273 146.881 ;
    END
  END r0_rd_out[47]
  PIN r0_rd_out[48]
    DIRECTION OUTPUT ;
    USE SIGNAL ;
    SHAPE ABUTMENT ;
    PORT
      LAYER M3 ;
      RECT 162.639 146.827 162.657 146.881 ;
    END
  END r0_rd_out[48]
  PIN r0_rd_out[49]
    DIRECTION OUTPUT ;
    USE SIGNAL ;
    SHAPE ABUTMENT ;
    PORT
      LAYER M3 ;
      RECT 166.023 146.827 166.041 146.881 ;
    END
  END r0_rd_out[49]
  PIN r0_rd_out[50]
    DIRECTION OUTPUT ;
    USE SIGNAL ;
    SHAPE ABUTMENT ;
    PORT
      LAYER M3 ;
      RECT 169.407 146.827 169.425 146.881 ;
    END
  END r0_rd_out[50]
  PIN r0_rd_out[51]
    DIRECTION OUTPUT ;
    USE SIGNAL ;
    SHAPE ABUTMENT ;
    PORT
      LAYER M3 ;
      RECT 172.791 146.827 172.809 146.881 ;
    END
  END r0_rd_out[51]
  PIN r0_rd_out[52]
    DIRECTION OUTPUT ;
    USE SIGNAL ;
    SHAPE ABUTMENT ;
    PORT
      LAYER M3 ;
      RECT 176.175 146.827 176.193 146.881 ;
    END
  END r0_rd_out[52]
  PIN r0_rd_out[53]
    DIRECTION OUTPUT ;
    USE SIGNAL ;
    SHAPE ABUTMENT ;
    PORT
      LAYER M3 ;
      RECT 179.559 146.827 179.577 146.881 ;
    END
  END r0_rd_out[53]
  PIN r0_rd_out[54]
    DIRECTION OUTPUT ;
    USE SIGNAL ;
    SHAPE ABUTMENT ;
    PORT
      LAYER M3 ;
      RECT 182.943 146.827 182.961 146.881 ;
    END
  END r0_rd_out[54]
  PIN r0_rd_out[55]
    DIRECTION OUTPUT ;
    USE SIGNAL ;
    SHAPE ABUTMENT ;
    PORT
      LAYER M3 ;
      RECT 186.327 146.827 186.345 146.881 ;
    END
  END r0_rd_out[55]
  PIN r0_rd_out[56]
    DIRECTION OUTPUT ;
    USE SIGNAL ;
    SHAPE ABUTMENT ;
    PORT
      LAYER M3 ;
      RECT 189.711 146.827 189.729 146.881 ;
    END
  END r0_rd_out[56]
  PIN r0_rd_out[57]
    DIRECTION OUTPUT ;
    USE SIGNAL ;
    SHAPE ABUTMENT ;
    PORT
      LAYER M3 ;
      RECT 193.095 146.827 193.113 146.881 ;
    END
  END r0_rd_out[57]
  PIN r0_rd_out[58]
    DIRECTION OUTPUT ;
    USE SIGNAL ;
    SHAPE ABUTMENT ;
    PORT
      LAYER M3 ;
      RECT 196.479 146.827 196.497 146.881 ;
    END
  END r0_rd_out[58]
  PIN r0_rd_out[59]
    DIRECTION OUTPUT ;
    USE SIGNAL ;
    SHAPE ABUTMENT ;
    PORT
      LAYER M3 ;
      RECT 199.863 146.827 199.881 146.881 ;
    END
  END r0_rd_out[59]
  PIN r0_rd_out[60]
    DIRECTION OUTPUT ;
    USE SIGNAL ;
    SHAPE ABUTMENT ;
    PORT
      LAYER M3 ;
      RECT 203.247 146.827 203.265 146.881 ;
    END
  END r0_rd_out[60]
  PIN r0_rd_out[61]
    DIRECTION OUTPUT ;
    USE SIGNAL ;
    SHAPE ABUTMENT ;
    PORT
      LAYER M3 ;
      RECT 206.631 146.827 206.649 146.881 ;
    END
  END r0_rd_out[61]
  PIN r0_rd_out[62]
    DIRECTION OUTPUT ;
    USE SIGNAL ;
    SHAPE ABUTMENT ;
    PORT
      LAYER M3 ;
      RECT 210.015 146.827 210.033 146.881 ;
    END
  END r0_rd_out[62]
  PIN r0_rd_out[63]
    DIRECTION OUTPUT ;
    USE SIGNAL ;
    SHAPE ABUTMENT ;
    PORT
      LAYER M3 ;
      RECT 213.399 146.827 213.417 146.881 ;
    END
  END r0_rd_out[63]
  PIN rw0_addr_in[0]
    DIRECTION INPUT ;
    USE SIGNAL ;
    SHAPE ABUTMENT ;
    PORT
      LAYER M4 ;
      RECT 0.000 90.132 0.072 90.156 ;
    END
  END rw0_addr_in[0]
  PIN rw0_addr_in[1]
    DIRECTION INPUT ;
    USE SIGNAL ;
    SHAPE ABUTMENT ;
    PORT
      LAYER M4 ;
      RECT 0.000 95.748 0.072 95.772 ;
    END
  END rw0_addr_in[1]
  PIN rw0_addr_in[2]
    DIRECTION INPUT ;
    USE SIGNAL ;
    SHAPE ABUTMENT ;
    PORT
      LAYER M4 ;
      RECT 0.000 101.364 0.072 101.388 ;
    END
  END rw0_addr_in[2]
  PIN rw0_addr_in[3]
    DIRECTION INPUT ;
    USE SIGNAL ;
    SHAPE ABUTMENT ;
    PORT
      LAYER M4 ;
      RECT 0.000 106.980 0.072 107.004 ;
    END
  END rw0_addr_in[3]
  PIN rw0_addr_in[4]
    DIRECTION INPUT ;
    USE SIGNAL ;
    SHAPE ABUTMENT ;
    PORT
      LAYER M4 ;
      RECT 0.000 112.596 0.072 112.620 ;
    END
  END rw0_addr_in[4]
  PIN rw0_addr_in[5]
    DIRECTION INPUT ;
    USE SIGNAL ;
    SHAPE ABUTMENT ;
    PORT
      LAYER M4 ;
      RECT 234.937 90.132 235.009 90.156 ;
    END
  END rw0_addr_in[5]
  PIN rw0_addr_in[6]
    DIRECTION INPUT ;
    USE SIGNAL ;
    SHAPE ABUTMENT ;
    PORT
      LAYER M4 ;
      RECT 234.937 95.748 235.009 95.772 ;
    END
  END rw0_addr_in[6]
  PIN rw0_addr_in[7]
    DIRECTION INPUT ;
    USE SIGNAL ;
    SHAPE ABUTMENT ;
    PORT
      LAYER M4 ;
      RECT 234.937 101.364 235.009 101.388 ;
    END
  END rw0_addr_in[7]
  PIN rw0_addr_in[8]
    DIRECTION INPUT ;
    USE SIGNAL ;
    SHAPE ABUTMENT ;
    PORT
      LAYER M4 ;
      RECT 234.937 106.980 235.009 107.004 ;
    END
  END rw0_addr_in[8]
  PIN rw0_addr_in[9]
    DIRECTION INPUT ;
    USE SIGNAL ;
    SHAPE ABUTMENT ;
    PORT
      LAYER M4 ;
      RECT 234.937 112.596 235.009 112.620 ;
    END
  END rw0_addr_in[9]
  PIN r0_addr_in[0]
    DIRECTION INPUT ;
    USE SIGNAL ;
    SHAPE ABUTMENT ;
    PORT
      LAYER M4 ;
      RECT 0.000 118.212 0.072 118.236 ;
    END
  END r0_addr_in[0]
  PIN r0_addr_in[1]
    DIRECTION INPUT ;
    USE SIGNAL ;
    SHAPE ABUTMENT ;
    PORT
      LAYER M4 ;
      RECT 0.000 123.828 0.072 123.852 ;
    END
  END r0_addr_in[1]
  PIN r0_addr_in[2]
    DIRECTION INPUT ;
    USE SIGNAL ;
    SHAPE ABUTMENT ;
    PORT
      LAYER M4 ;
      RECT 0.000 129.444 0.072 129.468 ;
    END
  END r0_addr_in[2]
  PIN r0_addr_in[3]
    DIRECTION INPUT ;
    USE SIGNAL ;
    SHAPE ABUTMENT ;
    PORT
      LAYER M4 ;
      RECT 0.000 135.060 0.072 135.084 ;
    END
  END r0_addr_in[3]
  PIN r0_addr_in[4]
    DIRECTION INPUT ;
    USE SIGNAL ;
    SHAPE ABUTMENT ;
    PORT
      LAYER M4 ;
      RECT 0.000 140.676 0.072 140.700 ;
    END
  END r0_addr_in[4]
  PIN r0_addr_in[5]
    DIRECTION INPUT ;
    USE SIGNAL ;
    SHAPE ABUTMENT ;
    PORT
      LAYER M4 ;
      RECT 234.937 118.212 235.009 118.236 ;
    END
  END r0_addr_in[5]
  PIN r0_addr_in[6]
    DIRECTION INPUT ;
    USE SIGNAL ;
    SHAPE ABUTMENT ;
    PORT
      LAYER M4 ;
      RECT 234.937 123.828 235.009 123.852 ;
    END
  END r0_addr_in[6]
  PIN r0_addr_in[7]
    DIRECTION INPUT ;
    USE SIGNAL ;
    SHAPE ABUTMENT ;
    PORT
      LAYER M4 ;
      RECT 234.937 129.444 235.009 129.468 ;
    END
  END r0_addr_in[7]
  PIN r0_addr_in[8]
    DIRECTION INPUT ;
    USE SIGNAL ;
    SHAPE ABUTMENT ;
    PORT
      LAYER M4 ;
      RECT 234.937 135.060 235.009 135.084 ;
    END
  END r0_addr_in[8]
  PIN r0_addr_in[9]
    DIRECTION INPUT ;
    USE SIGNAL ;
    SHAPE ABUTMENT ;
    PORT
      LAYER M4 ;
      RECT 234.937 140.676 235.009 140.700 ;
    END
  END r0_addr_in[9]
  PIN rw0_we_in
    DIRECTION INPUT ;
    USE SIGNAL ;
    SHAPE ABUTMENT ;
    PORT
      LAYER M3 ;
      RECT 216.783 146.827 216.801 146.881 ;
    END
  END rw0_we_in
  PIN rw0_ce_in
    DIRECTION INPUT ;
    USE SIGNAL ;
    SHAPE ABUTMENT ;
    PORT
      LAYER M3 ;
      RECT 220.167 146.827 220.185 146.881 ;
    END
  END rw0_ce_in
  PIN rw0_clk
    DIRECTION INPUT ;
    USE SIGNAL ;
    SHAPE ABUTMENT ;
    PORT
      LAYER M3 ;
      RECT 223.551 146.827 223.569 146.881 ;
    END
  END rw0_clk
  PIN r0_ce_in
    DIRECTION INPUT ;
    USE SIGNAL ;
    SHAPE ABUTMENT ;
    PORT
      LAYER M3 ;
      RECT 226.935 146.827 226.953 146.881 ;
    END
  END r0_ce_in
  PIN r0_clk
    DIRECTION INPUT ;
    USE SIGNAL ;
    SHAPE ABUTMENT ;
    PORT
      LAYER M3 ;
      RECT 230.319 146.827 230.337 146.881 ;
    END
  END r0_clk
  PIN VSS
    DIRECTION INOUT ;
    USE GROUND ;
    PORT
      LAYER M4 ;
      RECT 0.216 0.240 234.793 0.336 ;
      RECT 0.216 1.008 234.793 1.104 ;
      RECT 0.216 1.776 234.793 1.872 ;
      RECT 0.216 2.544 234.793 2.640 ;
      RECT 0.216 3.312 234.793 3.408 ;
      RECT 0.216 4.080 234.793 4.176 ;
      RECT 0.216 4.848 234.793 4.944 ;
      RECT 0.216 5.616 234.793 5.712 ;
      RECT 0.216 6.384 234.793 6.480 ;
      RECT 0.216 7.152 234.793 7.248 ;
      RECT 0.216 7.920 234.793 8.016 ;
      RECT 0.216 8.688 234.793 8.784 ;
      RECT 0.216 9.456 234.793 9.552 ;
      RECT 0.216 10.224 234.793 10.320 ;
      RECT 0.216 10.992 234.793 11.088 ;
      RECT 0.216 11.760 234.793 11.856 ;
      RECT 0.216 12.528 234.793 12.624 ;
      RECT 0.216 13.296 234.793 13.392 ;
      RECT 0.216 14.064 234.793 14.160 ;
      RECT 0.216 14.832 234.793 14.928 ;
      RECT 0.216 15.600 234.793 15.696 ;
      RECT 0.216 16.368 234.793 16.464 ;
      RECT 0.216 17.136 234.793 17.232 ;
      RECT 0.216 17.904 234.793 18.000 ;
      RECT 0.216 18.672 234.793 18.768 ;
      RECT 0.216 19.440 234.793 19.536 ;
      RECT 0.216 20.208 234.793 20.304 ;
      RECT 0.216 20.976 234.793 21.072 ;
      RECT 0.216 21.744 234.793 21.840 ;
      RECT 0.216 22.512 234.793 22.608 ;
      RECT 0.216 23.280 234.793 23.376 ;
      RECT 0.216 24.048 234.793 24.144 ;
      RECT 0.216 24.816 234.793 24.912 ;
      RECT 0.216 25.584 234.793 25.680 ;
      RECT 0.216 26.352 234.793 26.448 ;
      RECT 0.216 27.120 234.793 27.216 ;
      RECT 0.216 27.888 234.793 27.984 ;
      RECT 0.216 28.656 234.793 28.752 ;
      RECT 0.216 29.424 234.793 29.520 ;
      RECT 0.216 30.192 234.793 30.288 ;
      RECT 0.216 30.960 234.793 31.056 ;
      RECT 0.216 31.728 234.793 31.824 ;
      RECT 0.216 32.496 234.793 32.592 ;
      RECT 0.216 33.264 234.793 33.360 ;
      RECT 0.216 34.032 234.793 34.128 ;
      RECT 0.216 34.800 234.793 34.896 ;
      RECT 0.216 35.568 234.793 35.664 ;
      RECT 0.216 36.336 234.793 36.432 ;
      RECT 0.216 37.104 234.793 37.200 ;
      RECT 0.216 37.872 234.793 37.968 ;
      RECT 0.216 38.640 234.793 38.736 ;
      RECT 0.216 39.408 234.793 39.504 ;
      RECT 0.216 40.176 234.793 40.272 ;
      RECT 0.216 40.944 234.793 41.040 ;
      RECT 0.216 41.712 234.793 41.808 ;
      RECT 0.216 42.480 234.793 42.576 ;
      RECT 0.216 43.248 234.793 43.344 ;
      RECT 0.216 44.016 234.793 44.112 ;
      RECT 0.216 44.784 234.793 44.880 ;
      RECT 0.216 45.552 234.793 45.648 ;
      RECT 0.216 46.320 234.793 46.416 ;
      RECT 0.216 47.088 234.793 47.184 ;
      RECT 0.216 47.856 234.793 47.952 ;
      RECT 0.216 48.624 234.793 48.720 ;
      RECT 0.216 49.392 234.793 49.488 ;
      RECT 0.216 50.160 234.793 50.256 ;
      RECT 0.216 50.928 234.793 51.024 ;
      RECT 0.216 51.696 234.793 51.792 ;
      RECT 0.216 52.464 234.793 52.560 ;
      RECT 0.216 53.232 234.793 53.328 ;
      RECT 0.216 54.000 234.793 54.096 ;
      RECT 0.216 54.768 234.793 54.864 ;
      RECT 0.216 55.536 234.793 55.632 ;
      RECT 0.216 56.304 234.793 56.400 ;
      RECT 0.216 57.072 234.793 57.168 ;
      RECT 0.216 57.840 234.793 57.936 ;
      RECT 0.216 58.608 234.793 58.704 ;
      RECT 0.216 59.376 234.793 59.472 ;
      RECT 0.216 60.144 234.793 60.240 ;
      RECT 0.216 60.912 234.793 61.008 ;
      RECT 0.216 61.680 234.793 61.776 ;
      RECT 0.216 62.448 234.793 62.544 ;
      RECT 0.216 63.216 234.793 63.312 ;
      RECT 0.216 63.984 234.793 64.080 ;
      RECT 0.216 64.752 234.793 64.848 ;
      RECT 0.216 65.520 234.793 65.616 ;
      RECT 0.216 66.288 234.793 66.384 ;
      RECT 0.216 67.056 234.793 67.152 ;
      RECT 0.216 67.824 234.793 67.920 ;
      RECT 0.216 68.592 234.793 68.688 ;
      RECT 0.216 69.360 234.793 69.456 ;
      RECT 0.216 70.128 234.793 70.224 ;
      RECT 0.216 70.896 234.793 70.992 ;
      RECT 0.216 71.664 234.793 71.760 ;
      RECT 0.216 72.432 234.793 72.528 ;
      RECT 0.216 73.200 234.793 73.296 ;
      RECT 0.216 73.968 234.793 74.064 ;
      RECT 0.216 74.736 234.793 74.832 ;
      RECT 0.216 75.504 234.793 75.600 ;
      RECT 0.216 76.272 234.793 76.368 ;
      RECT 0.216 77.040 234.793 77.136 ;
      RECT 0.216 77.808 234.793 77.904 ;
      RECT 0.216 78.576 234.793 78.672 ;
      RECT 0.216 79.344 234.793 79.440 ;
      RECT 0.216 80.112 234.793 80.208 ;
      RECT 0.216 80.880 234.793 80.976 ;
      RECT 0.216 81.648 234.793 81.744 ;
      RECT 0.216 82.416 234.793 82.512 ;
      RECT 0.216 83.184 234.793 83.280 ;
      RECT 0.216 83.952 234.793 84.048 ;
      RECT 0.216 84.720 234.793 84.816 ;
      RECT 0.216 85.488 234.793 85.584 ;
      RECT 0.216 86.256 234.793 86.352 ;
      RECT 0.216 87.024 234.793 87.120 ;
      RECT 0.216 87.792 234.793 87.888 ;
      RECT 0.216 88.560 234.793 88.656 ;
      RECT 0.216 89.328 234.793 89.424 ;
      RECT 0.216 90.096 234.793 90.192 ;
      RECT 0.216 90.864 234.793 90.960 ;
      RECT 0.216 91.632 234.793 91.728 ;
      RECT 0.216 92.400 234.793 92.496 ;
      RECT 0.216 93.168 234.793 93.264 ;
      RECT 0.216 93.936 234.793 94.032 ;
      RECT 0.216 94.704 234.793 94.800 ;
      RECT 0.216 95.472 234.793 95.568 ;
      RECT 0.216 96.240 234.793 96.336 ;
      RECT 0.216 97.008 234.793 97.104 ;
      RECT 0.216 97.776 234.793 97.872 ;
      RECT 0.216 98.544 234.793 98.640 ;
      RECT 0.216 99.312 234.793 99.408 ;
      RECT 0.216 100.080 234.793 100.176 ;
      RECT 0.216 100.848 234.793 100.944 ;
      RECT 0.216 101.616 234.793 101.712 ;
      RECT 0.216 102.384 234.793 102.480 ;
      RECT 0.216 103.152 234.793 103.248 ;
      RECT 0.216 103.920 234.793 104.016 ;
      RECT 0.216 104.688 234.793 104.784 ;
      RECT 0.216 105.456 234.793 105.552 ;
      RECT 0.216 106.224 234.793 106.320 ;
      RECT 0.216 106.992 234.793 107.088 ;
      RECT 0.216 107.760 234.793 107.856 ;
      RECT 0.216 108.528 234.793 108.624 ;
      RECT 0.216 109.296 234.793 109.392 ;
      RECT 0.216 110.064 234.793 110.160 ;
      RECT 0.216 110.832 234.793 110.928 ;
      RECT 0.216 111.600 234.793 111.696 ;
      RECT 0.216 112.368 234.793 112.464 ;
      RECT 0.216 113.136 234.793 113.232 ;
      RECT 0.216 113.904 234.793 114.000 ;
      RECT 0.216 114.672 234.793 114.768 ;
      RECT 0.216 115.440 234.793 115.536 ;
      RECT 0.216 116.208 234.793 116.304 ;
      RECT 0.216 116.976 234.793 117.072 ;
      RECT 0.216 117.744 234.793 117.840 ;
      RECT 0.216 118.512 234.793 118.608 ;
      RECT 0.216 119.280 234.793 119.376 ;
      RECT 0.216 120.048 234.793 120.144 ;
      RECT 0.216 120.816 234.793 120.912 ;
      RECT 0.216 121.584 234.793 121.680 ;
      RECT 0.216 122.352 234.793 122.448 ;
      RECT 0.216 123.120 234.793 123.216 ;
      RECT 0.216 123.888 234.793 123.984 ;
      RECT 0.216 124.656 234.793 124.752 ;
      RECT 0.216 125.424 234.793 125.520 ;
      RECT 0.216 126.192 234.793 126.288 ;
      RECT 0.216 126.960 234.793 127.056 ;
      RECT 0.216 127.728 234.793 127.824 ;
      RECT 0.216 128.496 234.793 128.592 ;
      RECT 0.216 129.264 234.793 129.360 ;
      RECT 0.216 130.032 234.793 130.128 ;
      RECT 0.216 130.800 234.793 130.896 ;
      RECT 0.216 131.568 234.793 131.664 ;
      RECT 0.216 132.336 234.793 132.432 ;
      RECT 0.216 133.104 234.793 133.200 ;
      RECT 0.216 133.872 234.793 133.968 ;
      RECT 0.216 134.640 234.793 134.736 ;
      RECT 0.216 135.408 234.793 135.504 ;
      RECT 0.216 136.176 234.793 136.272 ;
      RECT 0.216 136.944 234.793 137.040 ;
      RECT 0.216 137.712 234.793 137.808 ;
      RECT 0.216 138.480 234.793 138.576 ;
      RECT 0.216 139.248 234.793 139.344 ;
      RECT 0.216 140.016 234.793 140.112 ;
      RECT 0.216 140.784 234.793 140.880 ;
      RECT 0.216 141.552 234.793 141.648 ;
      RECT 0.216 142.320 234.793 142.416 ;
      RECT 0.216 143.088 234.793 143.184 ;
      RECT 0.216 143.856 234.793 143.952 ;
      RECT 0.216 144.624 234.793 144.720 ;
      RECT 0.216 145.392 234.793 145.488 ;
      RECT 0.216 146.160 234.793 146.256 ;
    END
  END VSS
  PIN VDD
    DIRECTION INOUT ;
    USE POWER ;
    PORT
      LAYER M4 ;
      RECT 0.216 0.624 234.793 0.720 ;
      RECT 0.216 1.392 234.793 1.488 ;
      RECT 0.216 2.160 234.793 2.256 ;
      RECT 0.216 2.928 234.793 3.024 ;
      RECT 0.216 3.696 234.793 3.792 ;
      RECT 0.216 4.464 234.793 4.560 ;
      RECT 0.216 5.232 234.793 5.328 ;
      RECT 0.216 6.000 234.793 6.096 ;
      RECT 0.216 6.768 234.793 6.864 ;
      RECT 0.216 7.536 234.793 7.632 ;
      RECT 0.216 8.304 234.793 8.400 ;
      RECT 0.216 9.072 234.793 9.168 ;
      RECT 0.216 9.840 234.793 9.936 ;
      RECT 0.216 10.608 234.793 10.704 ;
      RECT 0.216 11.376 234.793 11.472 ;
      RECT 0.216 12.144 234.793 12.240 ;
      RECT 0.216 12.912 234.793 13.008 ;
      RECT 0.216 13.680 234.793 13.776 ;
      RECT 0.216 14.448 234.793 14.544 ;
      RECT 0.216 15.216 234.793 15.312 ;
      RECT 0.216 15.984 234.793 16.080 ;
      RECT 0.216 16.752 234.793 16.848 ;
      RECT 0.216 17.520 234.793 17.616 ;
      RECT 0.216 18.288 234.793 18.384 ;
      RECT 0.216 19.056 234.793 19.152 ;
      RECT 0.216 19.824 234.793 19.920 ;
      RECT 0.216 20.592 234.793 20.688 ;
      RECT 0.216 21.360 234.793 21.456 ;
      RECT 0.216 22.128 234.793 22.224 ;
      RECT 0.216 22.896 234.793 22.992 ;
      RECT 0.216 23.664 234.793 23.760 ;
      RECT 0.216 24.432 234.793 24.528 ;
      RECT 0.216 25.200 234.793 25.296 ;
      RECT 0.216 25.968 234.793 26.064 ;
      RECT 0.216 26.736 234.793 26.832 ;
      RECT 0.216 27.504 234.793 27.600 ;
      RECT 0.216 28.272 234.793 28.368 ;
      RECT 0.216 29.040 234.793 29.136 ;
      RECT 0.216 29.808 234.793 29.904 ;
      RECT 0.216 30.576 234.793 30.672 ;
      RECT 0.216 31.344 234.793 31.440 ;
      RECT 0.216 32.112 234.793 32.208 ;
      RECT 0.216 32.880 234.793 32.976 ;
      RECT 0.216 33.648 234.793 33.744 ;
      RECT 0.216 34.416 234.793 34.512 ;
      RECT 0.216 35.184 234.793 35.280 ;
      RECT 0.216 35.952 234.793 36.048 ;
      RECT 0.216 36.720 234.793 36.816 ;
      RECT 0.216 37.488 234.793 37.584 ;
      RECT 0.216 38.256 234.793 38.352 ;
      RECT 0.216 39.024 234.793 39.120 ;
      RECT 0.216 39.792 234.793 39.888 ;
      RECT 0.216 40.560 234.793 40.656 ;
      RECT 0.216 41.328 234.793 41.424 ;
      RECT 0.216 42.096 234.793 42.192 ;
      RECT 0.216 42.864 234.793 42.960 ;
      RECT 0.216 43.632 234.793 43.728 ;
      RECT 0.216 44.400 234.793 44.496 ;
      RECT 0.216 45.168 234.793 45.264 ;
      RECT 0.216 45.936 234.793 46.032 ;
      RECT 0.216 46.704 234.793 46.800 ;
      RECT 0.216 47.472 234.793 47.568 ;
      RECT 0.216 48.240 234.793 48.336 ;
      RECT 0.216 49.008 234.793 49.104 ;
      RECT 0.216 49.776 234.793 49.872 ;
      RECT 0.216 50.544 234.793 50.640 ;
      RECT 0.216 51.312 234.793 51.408 ;
      RECT 0.216 52.080 234.793 52.176 ;
      RECT 0.216 52.848 234.793 52.944 ;
      RECT 0.216 53.616 234.793 53.712 ;
      RECT 0.216 54.384 234.793 54.480 ;
      RECT 0.216 55.152 234.793 55.248 ;
      RECT 0.216 55.920 234.793 56.016 ;
      RECT 0.216 56.688 234.793 56.784 ;
      RECT 0.216 57.456 234.793 57.552 ;
      RECT 0.216 58.224 234.793 58.320 ;
      RECT 0.216 58.992 234.793 59.088 ;
      RECT 0.216 59.760 234.793 59.856 ;
      RECT 0.216 60.528 234.793 60.624 ;
      RECT 0.216 61.296 234.793 61.392 ;
      RECT 0.216 62.064 234.793 62.160 ;
      RECT 0.216 62.832 234.793 62.928 ;
      RECT 0.216 63.600 234.793 63.696 ;
      RECT 0.216 64.368 234.793 64.464 ;
      RECT 0.216 65.136 234.793 65.232 ;
      RECT 0.216 65.904 234.793 66.000 ;
      RECT 0.216 66.672 234.793 66.768 ;
      RECT 0.216 67.440 234.793 67.536 ;
      RECT 0.216 68.208 234.793 68.304 ;
      RECT 0.216 68.976 234.793 69.072 ;
      RECT 0.216 69.744 234.793 69.840 ;
      RECT 0.216 70.512 234.793 70.608 ;
      RECT 0.216 71.280 234.793 71.376 ;
      RECT 0.216 72.048 234.793 72.144 ;
      RECT 0.216 72.816 234.793 72.912 ;
      RECT 0.216 73.584 234.793 73.680 ;
      RECT 0.216 74.352 234.793 74.448 ;
      RECT 0.216 75.120 234.793 75.216 ;
      RECT 0.216 75.888 234.793 75.984 ;
      RECT 0.216 76.656 234.793 76.752 ;
      RECT 0.216 77.424 234.793 77.520 ;
      RECT 0.216 78.192 234.793 78.288 ;
      RECT 0.216 78.960 234.793 79.056 ;
      RECT 0.216 79.728 234.793 79.824 ;
      RECT 0.216 80.496 234.793 80.592 ;
      RECT 0.216 81.264 234.793 81.360 ;
      RECT 0.216 82.032 234.793 82.128 ;
      RECT 0.216 82.800 234.793 82.896 ;
      RECT 0.216 83.568 234.793 83.664 ;
      RECT 0.216 84.336 234.793 84.432 ;
      RECT 0.216 85.104 234.793 85.200 ;
      RECT 0.216 85.872 234.793 85.968 ;
      RECT 0.216 86.640 234.793 86.736 ;
      RECT 0.216 87.408 234.793 87.504 ;
      RECT 0.216 88.176 234.793 88.272 ;
      RECT 0.216 88.944 234.793 89.040 ;
      RECT 0.216 89.712 234.793 89.808 ;
      RECT 0.216 90.480 234.793 90.576 ;
      RECT 0.216 91.248 234.793 91.344 ;
      RECT 0.216 92.016 234.793 92.112 ;
      RECT 0.216 92.784 234.793 92.880 ;
      RECT 0.216 93.552 234.793 93.648 ;
      RECT 0.216 94.320 234.793 94.416 ;
      RECT 0.216 95.088 234.793 95.184 ;
      RECT 0.216 95.856 234.793 95.952 ;
      RECT 0.216 96.624 234.793 96.720 ;
      RECT 0.216 97.392 234.793 97.488 ;
      RECT 0.216 98.160 234.793 98.256 ;
      RECT 0.216 98.928 234.793 99.024 ;
      RECT 0.216 99.696 234.793 99.792 ;
      RECT 0.216 100.464 234.793 100.560 ;
      RECT 0.216 101.232 234.793 101.328 ;
      RECT 0.216 102.000 234.793 102.096 ;
      RECT 0.216 102.768 234.793 102.864 ;
      RECT 0.216 103.536 234.793 103.632 ;
      RECT 0.216 104.304 234.793 104.400 ;
      RECT 0.216 105.072 234.793 105.168 ;
      RECT 0.216 105.840 234.793 105.936 ;
      RECT 0.216 106.608 234.793 106.704 ;
      RECT 0.216 107.376 234.793 107.472 ;
      RECT 0.216 108.144 234.793 108.240 ;
      RECT 0.216 108.912 234.793 109.008 ;
      RECT 0.216 109.680 234.793 109.776 ;
      RECT 0.216 110.448 234.793 110.544 ;
      RECT 0.216 111.216 234.793 111.312 ;
      RECT 0.216 111.984 234.793 112.080 ;
      RECT 0.216 112.752 234.793 112.848 ;
      RECT 0.216 113.520 234.793 113.616 ;
      RECT 0.216 114.288 234.793 114.384 ;
      RECT 0.216 115.056 234.793 115.152 ;
      RECT 0.216 115.824 234.793 115.920 ;
      RECT 0.216 116.592 234.793 116.688 ;
      RECT 0.216 117.360 234.793 117.456 ;
      RECT 0.216 118.128 234.793 118.224 ;
      RECT 0.216 118.896 234.793 118.992 ;
      RECT 0.216 119.664 234.793 119.760 ;
      RECT 0.216 120.432 234.793 120.528 ;
      RECT 0.216 121.200 234.793 121.296 ;
      RECT 0.216 121.968 234.793 122.064 ;
      RECT 0.216 122.736 234.793 122.832 ;
      RECT 0.216 123.504 234.793 123.600 ;
      RECT 0.216 124.272 234.793 124.368 ;
      RECT 0.216 125.040 234.793 125.136 ;
      RECT 0.216 125.808 234.793 125.904 ;
      RECT 0.216 126.576 234.793 126.672 ;
      RECT 0.216 127.344 234.793 127.440 ;
      RECT 0.216 128.112 234.793 128.208 ;
      RECT 0.216 128.880 234.793 128.976 ;
      RECT 0.216 129.648 234.793 129.744 ;
      RECT 0.216 130.416 234.793 130.512 ;
      RECT 0.216 131.184 234.793 131.280 ;
      RECT 0.216 131.952 234.793 132.048 ;
      RECT 0.216 132.720 234.793 132.816 ;
      RECT 0.216 133.488 234.793 133.584 ;
      RECT 0.216 134.256 234.793 134.352 ;
      RECT 0.216 135.024 234.793 135.120 ;
      RECT 0.216 135.792 234.793 135.888 ;
      RECT 0.216 136.560 234.793 136.656 ;
      RECT 0.216 137.328 234.793 137.424 ;
      RECT 0.216 138.096 234.793 138.192 ;
      RECT 0.216 138.864 234.793 138.960 ;
      RECT 0.216 139.632 234.793 139.728 ;
      RECT 0.216 140.400 234.793 140.496 ;
      RECT 0.216 141.168 234.793 141.264 ;
      RECT 0.216 141.936 234.793 142.032 ;
      RECT 0.216 142.704 234.793 142.800 ;
      RECT 0.216 143.472 234.793 143.568 ;
      RECT 0.216 144.240 234.793 144.336 ;
      RECT 0.216 145.008 234.793 145.104 ;
      RECT 0.216 145.776 234.793 145.872 ;
      RECT 0.216 146.544 234.793 146.640 ;
    END
  END VDD
  OBS
    LAYER M1 ;
    RECT 0 0 235.009 146.881 ;
    LAYER M2 ;
    RECT 0 0 235.009 146.881 ;
    LAYER M3 ;
    RECT 0 0 235.009 146.881 ;
    LAYER M4 ;
    RECT 0 0 235.009 146.881 ;
  END
END fakeram_1rw1r_64w1024d_sram

END LIBRARY
